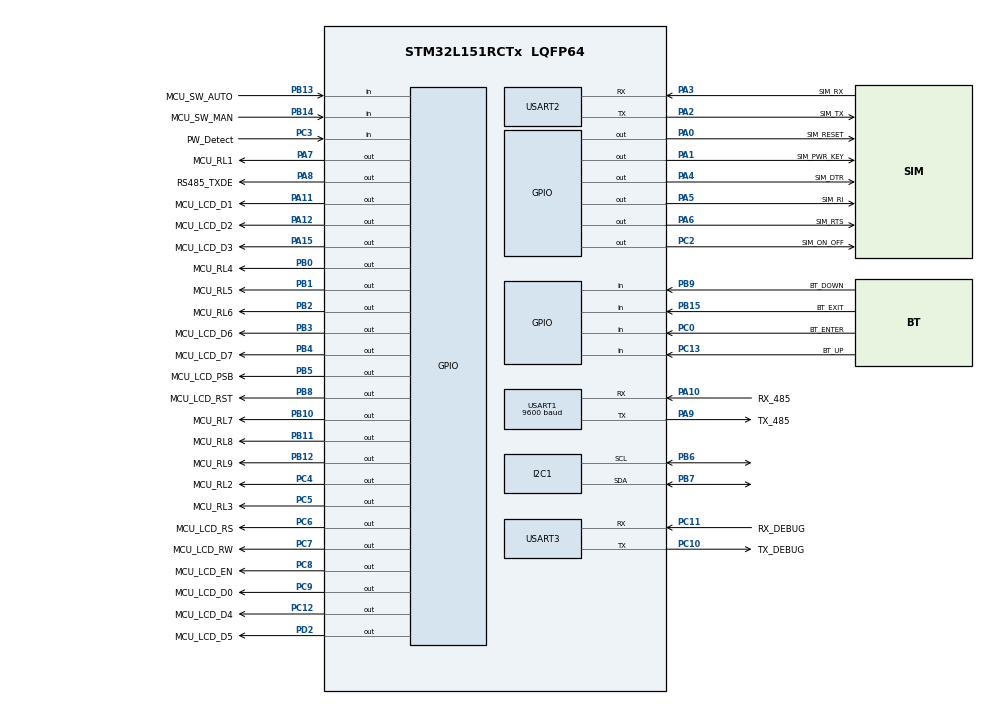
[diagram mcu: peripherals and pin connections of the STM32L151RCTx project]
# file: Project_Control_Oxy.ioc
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Dma.Request0=USART1_RX
Dma.Request1=USART2_RX
Dma.Request2=USART3_RX
Dma.USART1_RX.0.Direction=DMA_PERIPH_TO_MEMORY
Dma.USART1_RX.0.Instance=DMA1_Channel5
Dma.USART1_RX.0.MemDataAlignment=DMA_MDATAALIGN_BYTE
Dma.USART1_RX.0.MemInc=DMA_MINC_ENABLE
Dma.USART1_RX.0.Mode=DMA_CIRCULAR
Dma.USART1_RX.0.PeriphDataAlignment=DMA_PDATAALIGN_BYTE
Dma.USART1_RX.0.PeriphInc=DMA_PINC_DISABLE
Dma.USART1_RX.0.Priority=DMA_PRIORITY_LOW
Dma.USART2_RX.1.Direction=DMA_PERIPH_TO_MEMORY
Dma.USART2_RX.1.Instance=DMA1_Channel6
Dma.USART2_RX.1.MemDataAlignment=DMA_MDATAALIGN_BYTE
Dma.USART2_RX.1.MemInc=DMA_MINC_ENABLE
Dma.USART2_RX.1.Mode=DMA_CIRCULAR
Dma.USART2_RX.1.PeriphDataAlignment=DMA_PDATAALIGN_BYTE
Dma.USART2_RX.1.PeriphInc=DMA_PINC_DISABLE
Dma.USART2_RX.1.Priority=DMA_PRIORITY_LOW
Dma.USART3_RX.2.Direction=DMA_PERIPH_TO_MEMORY
Dma.USART3_RX.2.Instance=DMA1_Channel3
Dma.USART3_RX.2.MemDataAlignment=DMA_MDATAALIGN_BYTE
Dma.USART3_RX.2.MemInc=DMA_MINC_ENABLE
Dma.USART3_RX.2.Mode=DMA_CIRCULAR
Dma.USART3_RX.2.PeriphDataAlignment=DMA_PDATAALIGN_BYTE
Dma.USART3_RX.2.PeriphInc=DMA_PINC_DISABLE
Dma.USART3_RX.2.Priority=DMA_PRIORITY_LOW
IWDG.Prescaler=IWDG_PRESCALER_256
IWDG.Reload=722
Mcu.Family=STM32L1
Mcu.Name=STM32L151RCTx
Mcu.Package=LQFP64
NVIC.DMA1_Channel3_IRQn=true\:0\:0\:false\:false\:true\:false\:true\:true
NVIC.DMA1_Channel5_IRQn=true\:0\:0\:false\:false\:true\:false\:true\:true
NVIC.DMA1_Channel6_IRQn=true\:0\:0\:false\:false\:true\:false\:true\:true
NVIC.PriorityGroup=NVIC_PRIORITYGROUP_4
NVIC.RTC_Alarm_IRQn=true\:0\:0\:false\:false\:true\:true\:true\:true
NVIC.USART1_IRQn=true\:0\:0\:false\:false\:true\:true\:true\:true
NVIC.USART2_IRQn=true\:0\:0\:false\:false\:true\:true\:true\:true
NVIC.USART3_IRQn=true\:0\:0\:false\:false\:true\:true\:true\:true
PA0-WKUP1.GPIO_Label=SIM_RESET
PA0-WKUP1.Signal=GPIO_Output
PA1.GPIO_Label=SIM_PWR_KEY
PA1.Signal=GPIO_Output
PA10.GPIO_Label=RX_485
PA10.Mode=Asynchronous
PA10.Signal=USART1_RX
PA11.GPIO_Label=MCU_LCD_D1
PA11.Signal=GPIO_Output
PA12.GPIO_Label=MCU_LCD_D2
PA12.Signal=GPIO_Output
PA13.Mode=Serial_Wire
PA13.Signal=SYS_JTMS-SWDIO
PA14.Mode=Serial_Wire
PA14.Signal=SYS_JTCK-SWCLK
PA15.GPIO_Label=MCU_LCD_D3
PA15.Signal=GPIO_Output
PA2.GPIO_Label=SIM_TX
PA2.Mode=Asynchronous
PA2.Signal=USART2_TX
PA3.GPIO_Label=SIM_RX
PA3.Mode=Asynchronous
PA3.Signal=USART2_RX
PA4.GPIO_Label=SIM_DTR
PA4.Signal=GPIO_Output
PA5.GPIO_Label=SIM_RI
PA5.Signal=GPIO_Output
PA6.GPIO_Label=SIM_RTS
PA6.Signal=GPIO_Output
PA7.GPIO_Label=MCU_RL1
PA7.Signal=GPIO_Output
PA8.GPIO_Label=RS485_TXDE
PA8.Signal=GPIO_Output
PA9.GPIO_Label=TX_485
PA9.Mode=Asynchronous
PA9.Signal=USART1_TX
PB0.GPIO_Label=MCU_RL4
PB0.Signal=GPIO_Output
PB1.GPIO_Label=MCU_RL5
PB1.Signal=GPIO_Output
PB10.GPIO_Label=MCU_RL7
PB10.Signal=GPIO_Output
PB11.GPIO_Label=MCU_RL8
PB11.Signal=GPIO_Output
PB12.GPIO_Label=MCU_RL9
PB12.Signal=GPIO_Output
PB13.GPIO_Label=MCU_SW_AUTO
PB13.GPIO_PuPd=GPIO_PULLUP
PB13.Signal=GPIO_Input
PB14.GPIO_Label=MCU_SW_MAN
PB14.GPIO_PuPd=GPIO_PULLUP
PB14.Signal=GPIO_Input
PB15.GPIO_Label=BT_EXIT
PB15.GPIO_PuPd=GPIO_PULLUP
PB15.Signal=GPIO_Input
PB2.GPIO_Label=MCU_RL6
PB2.Signal=GPIO_Output
PB3.GPIO_Label=MCU_LCD_D6
PB3.Signal=GPIO_Output
PB4.GPIO_Label=MCU_LCD_D7
PB4.Signal=GPIO_Output
PB5.GPIO_Label=MCU_LCD_PSB
PB5.Signal=GPIO_Output
PB6.Mode=I2C
PB6.Signal=I2C1_SCL
PB7.Mode=I2C
PB7.Signal=I2C1_SDA
PB8.GPIO_Label=MCU_LCD_RST
PB8.Signal=GPIO_Output
PB9.GPIO_Label=BT_DOWN
PB9.GPIO_PuPd=GPIO_PULLUP
PB9.Signal=GPIO_Input
PC0.GPIO_Label=BT_ENTER
PC0.GPIO_PuPd=GPIO_PULLUP
PC0.Signal=GPIO_Input
PC10.GPIO_Label=TX_DEBUG
PC10.Mode=Asynchronous
PC10.Signal=USART3_TX
PC11.GPIO_Label=RX_DEBUG
PC11.Mode=Asynchronous
PC11.Signal=USART3_RX
PC12.GPIO_Label=MCU_LCD_D4
PC12.Signal=GPIO_Output
PC13-WKUP2.GPIO_Label=BT_UP
PC13-WKUP2.GPIO_PuPd=GPIO_PULLUP
PC13-WKUP2.Signal=GPIO_Input
PC14-OSC32_IN.Mode=LSE-External-Oscillator
PC14-OSC32_IN.Signal=RCC_OSC32_IN
PC15-OSC32_OUT.Mode=LSE-External-Oscillator
PC15-OSC32_OUT.Signal=RCC_OSC32_OUT
PC2.GPIO_Label=SIM_ON_OFF
PC2.Signal=GPIO_Output
PC3.GPIO_Label=PW_Detect
PC3.Signal=GPIO_Input
PC4.GPIO_Label=MCU_RL2
PC4.Signal=GPIO_Output
PC5.GPIO_Label=MCU_RL3
PC5.Signal=GPIO_Output
PC6.GPIO_Label=MCU_LCD_RS
PC6.Signal=GPIO_Output
PC7.GPIO_Label=MCU_LCD_RW
PC7.Signal=GPIO_Output
PC8.GPIO_Label=MCU_LCD_EN
PC8.Signal=GPIO_Output
PC9.GPIO_Label=MCU_LCD_D0
PC9.Signal=GPIO_Output
PD2.GPIO_Label=MCU_LCD_D5
PD2.Signal=GPIO_Output
ProjectManager.HeapSize=0x200
ProjectManager.StackSize=0x400
ProjectManager.TargetToolchain=EWARM V8.32
RCC.AHBFreq_Value=24000000
RCC.APB1Freq_Value=24000000
RCC.APB1TimFreq_Value=24000000
RCC.APB2Freq_Value=24000000
RCC.APB2TimFreq_Value=24000000
RCC.HCLKFreq_Value=24000000
RCC.HSE_VALUE=24000000
RCC.HSI_VALUE=16000000
RCC.MSI_VALUE=2097000
RCC.RTCClockSelectionVirtual=RCC_RTCCLKSOURCE_LSE
RCC.SYSCLKFreq_VALUE=24000000
RCC.SYSCLKSource=RCC_SYSCLKSOURCE_PLLCLK
RCC.VCOOutputFreq_Value=48000000
RTC.Alarm-Alarm\ A=RTC_ALARM_A
RTC.Format=RTC_FORMAT_BIN
USART1.BaudRate=9600
USART1.StopBits=STOPBITS_2
USART1.VirtualMode=VM_ASYNC
USART2.VirtualMode=VM_ASYNC
USART3.VirtualMode=VM_ASYNC
VP_IWDG_VS_IWDG.Mode=IWDG_Activate
VP_RTC_VS_RTC_Activate.Mode=RTC_Enabled
VP_RTC_VS_RTC_Alarm_A_Intern.Mode=Alarm A
VP_RTC_VS_RTC_Calendar.Mode=RTC_Calendar
board=custom

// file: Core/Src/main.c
/* USER CODE BEGIN Header */
/**
  ******************************************************************************
  * @file           : main.c
  * @brief          : Main program body
  ******************************************************************************
  * @attention
  *
  * Copyright (c) 2023 STMicroelectronics.
  * All rights reserved.
  *
  * This software is licensed under terms that can be found in the LICENSE file
  * in the root directory of this software component.
  * If no LICENSE file comes with this software, it is provided AS-IS.
  *
  ******************************************************************************
  */
/* USER CODE END Header */
#include "main.h"
#include "dma.h"
#include "i2c.h"
#include "iwdg.h"
#include "rtc.h"
#include "usart.h"
#include "gpio.h"

/* USER CODE BEGIN Includes */
#include "user_app_comm.h"
/* USER CODE END Includes */

/* USER CODE BEGIN PTD */
#include "user_sim.h"
#include "user_internal_mem.h"

/* USER CODE END PTD */

/* USER CODE BEGIN PD */
#include "cat24mxx.h"
/* USER CODE END PD */

void SystemClock_Config(void);

int main(void)
{
  /* USER CODE BEGIN 1 */
  SCB -> VTOR = ADDR_MAIN_PROGRAM;
  /* USER CODE END 1 */

  /* MCU Configuration--------------------------------------------------------*/

  /* Reset of all peripherals, Initializes the Flash interface and the Systick. */
  HAL_Init();

  /* Configure the system clock */
  SystemClock_Config();

  /* Initialize all configured peripherals */
  MX_GPIO_Init();
  MX_DMA_Init();
  MX_I2C1_Init();
  MX_RTC_Init();
  MX_USART1_UART_Init();
  MX_USART2_UART_Init();
  MX_USART3_UART_Init();
  MX_IWDG_Init();
  /* USER CODE BEGIN 2 */
  Main_Task();
  /* USER CODE END 2 */

  /* Infinite loop */
  while (1)
  {

  }
}

void SystemClock_Config(void)
{
  RCC_OscInitTypeDef RCC_OscInitStruct = {0};
  RCC_ClkInitTypeDef RCC_ClkInitStruct = {0};
  RCC_PeriphCLKInitTypeDef PeriphClkInit = {0};

  /** Configure the main internal regulator output voltage
  */
  __HAL_PWR_VOLTAGESCALING_CONFIG(PWR_REGULATOR_VOLTAGE_SCALE1);

  /** Initializes the RCC Oscillators according to the specified parameters
  * in the RCC_OscInitTypeDef structure.
  */
  RCC_OscInitStruct.OscillatorType = RCC_OSCILLATORTYPE_HSI|RCC_OSCILLATORTYPE_LSI
                              |RCC_OSCILLATORTYPE_LSE;
  RCC_OscInitStruct.LSEState = RCC_LSE_ON;
  RCC_OscInitStruct.HSIState = RCC_HSI_ON;
  RCC_OscInitStruct.HSICalibrationValue = RCC_HSICALIBRATION_DEFAULT;
  RCC_OscInitStruct.LSIState = RCC_LSI_ON;
  RCC_OscInitStruct.PLL.PLLState = RCC_PLL_ON;
  RCC_OscInitStruct.PLL.PLLSource = RCC_PLLSOURCE_HSI;
  RCC_OscInitStruct.PLL.PLLMUL = RCC_PLL_MUL4;
  RCC_OscInitStruct.PLL.PLLDIV = RCC_PLL_DIV2;
  if (HAL_RCC_OscConfig(&RCC_OscInitStruct) != HAL_OK)
  {
    Error_Handler();
  }

  /** Initializes the CPU, AHB and APB buses clocks
  */
  RCC_ClkInitStruct.ClockType = RCC_CLOCKTYPE_HCLK|RCC_CLOCKTYPE_SYSCLK
                              |RCC_CLOCKTYPE_PCLK1|RCC_CLOCKTYPE_PCLK2;
  RCC_ClkInitStruct.SYSCLKSource = RCC_SYSCLKSOURCE_PLLCLK;
  RCC_ClkInitStruct.AHBCLKDivider = RCC_SYSCLK_DIV1;
  RCC_ClkInitStruct.APB1CLKDivider = RCC_HCLK_DIV1;
  RCC_ClkInitStruct.APB2CLKDivider = RCC_HCLK_DIV1;

  if (HAL_RCC_ClockConfig(&RCC_ClkInitStruct, FLASH_LATENCY_1) != HAL_OK)
  {
    Error_Handler();
  }
  PeriphClkInit.PeriphClockSelection = RCC_PERIPHCLK_RTC;
  PeriphClkInit.RTCClockSelection = RCC_RTCCLKSOURCE_LSE;
  if (HAL_RCCEx_PeriphCLKConfig(&PeriphClkInit) != HAL_OK)
  {
    Error_Handler();
  }
}

void Error_Handler(void)
{
  __disable_irq();
  while (1)
  {
  }
}
